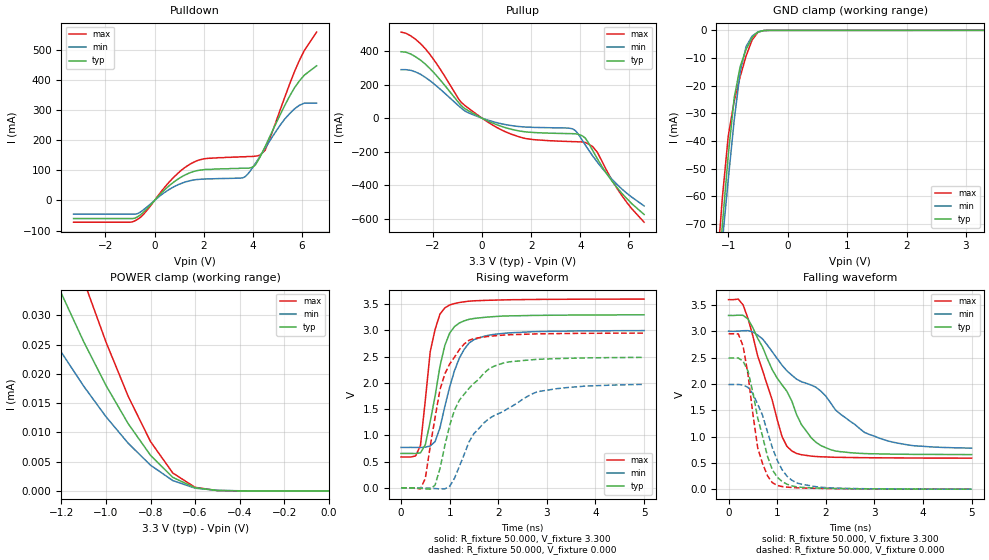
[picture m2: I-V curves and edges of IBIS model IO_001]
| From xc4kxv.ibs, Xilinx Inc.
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|   Model IO_001
[Model]   IO_001
Model_type   I/O
Polarity   Inverting
Enable   Active-High
Vinl =   0.800V
Vinh =   2.000V
Vmeas =   1.650V
Cref =  50.000pF
Rref =   1.000M
Vref =  0.000V
C_comp   7.800pF   6.700pF   8.800pF
[Temperature Range]   50.000   100.000   0.000
[Voltage Range]   3.300V   3.000V   3.600V
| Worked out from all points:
|   slope of the pulldown table from 0 to 0.495 V, typ, clamps not added: 11.9 ohm
|   slope of the pullup table from 0 to 0.495 V, typ, clamps not added: 15 ohm
|   GND clamp passes 1 mA (typ) near -0.52 V on its own axis
|   POWER clamp passes 1 mA (typ) near -2.17 V on its own axis
|   rising waveform, R_fixture 50.000, V_fixture 3.300: 20-80 % time 343ps typ, 429ps min, 251ps max; typ from 0.655 V to 3.3 V
|   rising waveform, R_fixture 50.000, V_fixture 0.000: 20-80 % time 667ps typ, 1.13ns min, 433ps max; typ from 0 V to 2.48 V
|   falling waveform, R_fixture 50.000, V_fixture 3.300: 20-80 % time 876ps typ, 1.66ns min, 567ps max; typ from 3.3 V to 0.659 V
|   falling waveform, R_fixture 50.000, V_fixture 0.000: 20-80 % time 389ps typ, 475ps min, 299ps max; typ from 2.49 V to 0.002 V
[Pulldown]
| voltage   I(typ)   I(min)   I(max)
-3.3V     -60.2mA    -45.6mA    -72.29mA
-900mV    -60.2mA    -45.6mA    -71.15mA
-500mV    -42.78mA   -34.12mA   -50.34mA
700mV     55.86mA    41.45mA    70.07mA
1.5V      93.58mA    66.46mA    123mA
3.6V      107mA      75.22mA    145mA
4V        111mA      110mA      146mA
4.3V      145mA      147mA      151mA
4.5V      178mA      173mA      166mA
5.7V      374mA      304mA      428mA
6.1V      416mA      323mA      498mA
6.6V      447mA      323mA      559mA
[Pullup]
| voltage   I(typ)   I(min)   I(max)
-3.3V     396mA      289mA      513mA
-2.9V     382mA      285mA      490mA
-2.3V     321mA      242mA      412mA
-800mV    68.22mA    54.08mA    87.71mA
400mV     -27.34mA   -18.89mA   -38.44mA
1.7V      -80.31mA   -52.16mA   -119mA
3.6V      -92.22mA   -60.85mA   -139mA
3.8V      -93.34mA   -74.12mA   -140mA
4.1V      -107mA     -136mA     -142mA
4.7V      -243mA     -263mA     -204mA
5.7V      -449mA     -423mA     -463mA
6.6V      -574mA     -523mA     -620mA
[GND_clamp]
| voltage   I(typ)   I(min)   I(max)
-3.3V     -475mA     -431mA     -510mA
-1.2V     -96.91mA   -99.09mA   -88.66mA
-1.1V     -70.47mA   -76.48mA   -60.6mA
-1V       -45.03mA   -53.86mA   -38.11mA
-900mV    -24.36mA   -32.38mA   -25.58mA
-800mV    -13.12mA   -15.05mA   -16.78mA
-700mV    -6.877mA   -5.864mA   -9.257mA
-600mV    -2.638mA   -2.119mA   -3.553mA
-500mV    -566uA     -554uA     -665uA
-400mV    -66.96uA   -103uA     -53.9uA
-300mV    -8.622uA   -14.21uA   -13.77uA
3.3V      2.571nA    15.57nA    666pA
[POWER_clamp]
| voltage   I(typ)   I(min)   I(max)
-3.3V     8.348mA    6.078mA    9.969mA
-1.4V     52.17uA    36.82uA    72.84uA
-1.3V     42.63uA    29.94uA    59.76uA
-1.2V     33.71uA    23.66uA    47.42uA
-1.1V     25.48uA    17.89uA    35.93uA
-1V       18.02uA    12.68uA    25.43uA
-900mV    11.47uA    8.13uA     16.14uA
-800mV    6.082uA    4.396uA    8.428uA
-700mV    2.312uA    1.764uA    3.06uA
-600mV    537nA      470nA      614nA
-500mV    77.35nA    96.49nA    62.62nA
0V        2.571nA    11.85nA    731pA
[Ramp]
| variable   typ   min   max
dV/dt_r   1.491/0.691n   1.183/1.149n   1.769/0.402n
dV/dt_f   1.585/0.880n   1.331/1.666n   1.805/0.536n
R_load = 50.000
[Rising Waveform]
R_fixture = 50.000
V_fixture = 3.300
V_fixture_min = 3.000
V_fixture_max = 3.600
L_fixture = 0.000H
C_fixture = 0.000F
| time   V(typ)   V(min)   V(max)
0s        655mV      770mV      588mV
300ps     654mV      770mV      608mV
400ps     666mV      769mV      809mV
500ps     823mV      775mV      1.678V
600ps     1.265V     798mV      2.595V
700ps     1.746V     881mV      3.018V
900ps     2.711V     1.549V     3.429V
1.2ns     3.142V     2.473V     3.532V
1.5ns     3.227V     2.824V     3.564V
5ns       3.297V     2.996V     3.597V
[Rising Waveform]
R_fixture = 50.000
V_fixture = 0.000
V_fixture_min = 0.000
V_fixture_max = 0.000
L_fixture = 0.000H
C_fixture = 0.000F
| time   V(typ)   V(min)   V(max)
0s        0V         0V         0V
400ps     -8.187mV   -395uV     -20.02mV
500ps     -18.9mV    -3.482mV   183mV
700ps     53.19mV    -13.5mV    1.341V
900ps     801mV      -20.23mV   2.171V
1.1ns     1.481V     183mV      2.491V
1.4ns     1.898V     879mV      2.813V
1.9ns     2.312V     1.37V      2.895V
2.8ns     2.448V     1.828V     2.934V
5ns       2.485V     1.971V     2.948V
[Falling Waveform]
R_fixture = 50.000
V_fixture = 3.300
V_fixture_min = 3.000
V_fixture_max = 3.600
L_fixture = 0.000H
C_fixture = 0.000F
| time   V(typ)   V(min)   V(max)
0s        3.3V       3V         3.6V
300ps     3.302V     3.01V      3.498V
700ps     2.7V       2.854V     2.255V
1.1ns     1.982V     2.356V     1.001V
1.3ns     1.678V     2.167V     729mV
1.7ns     978mV      1.979V     630mV
2.1ns     752mV      1.64V      610mV
2.8ns     678mV      1.078V     600mV
3.2ns     670mV      940mV      597mV
5ns       659mV      782mV      591mV
[Falling Waveform]
R_fixture = 50.000
V_fixture = 0.000
V_fixture_min = 0.000
V_fixture_max = 0.000
L_fixture = 0.000H
C_fixture = 0.000F
| time   V(typ)   V(min)   V(max)
0s        2.492V     1.989V     2.952V
200ps     2.492V     1.99V      2.95V
300ps     2.431V     1.979V     2.717V
400ps     2.243V     1.935V     2.178V
600ps     1.352V     1.613V     785mV
800ps     629mV      1.089V     258mV
900ps     373mV      793mV      127mV
1.2ns     97.08mV    251mV      41.53mV
1.5ns     37.18mV    96.16mV    24.69mV
5ns       2.351mV    2.484mV    2.349mV
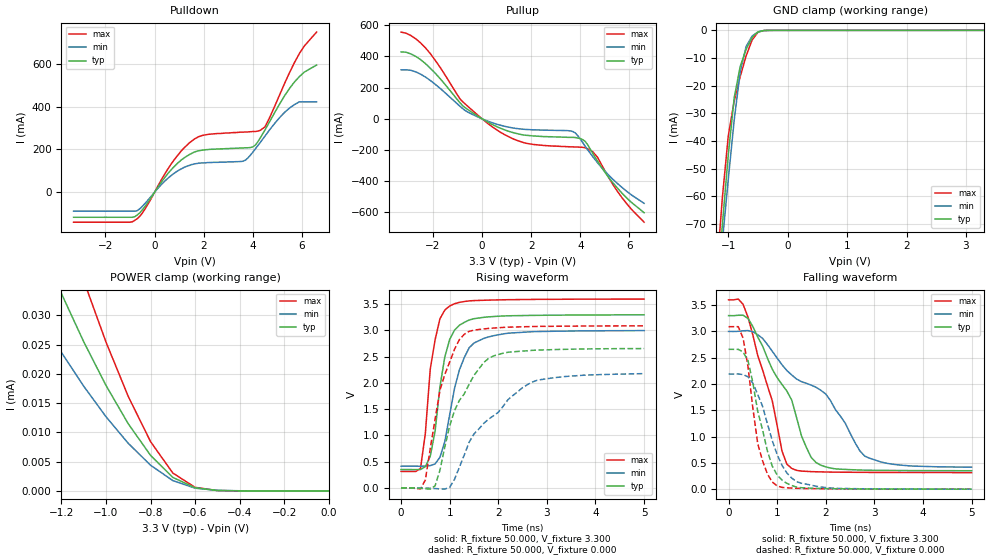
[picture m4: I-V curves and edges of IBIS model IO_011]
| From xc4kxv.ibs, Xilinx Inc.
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|   Model IO_011
[Model]   IO_011
Model_type   I/O
Polarity   Inverting
Enable   Active-High
Vinl =   0.800V
Vinh =   2.000V
Vmeas =   1.650V
Cref =  50.000pF
Rref =   1.000M
Vref =  0.000V
C_comp   7.800pF   6.700pF   8.800pF
[Temperature Range]   50.000   100.000   0.000
[Voltage Range]   3.300V   3.000V   3.600V
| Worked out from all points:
|   slope of the pulldown table from 0 to 0.495 V, typ, clamps not added: 6.14 ohm
|   slope of the pullup table from 0 to 0.495 V, typ, clamps not added: 11.6 ohm
|   GND clamp passes 1 mA (typ) near -0.52 V on its own axis
|   POWER clamp passes 1 mA (typ) near -2.17 V on its own axis
|   rising waveform, R_fixture 50.000, V_fixture 3.300: 20-80 % time 293ps typ, 390ps min, 240ps max; typ from 0.35 V to 3.3 V
|   rising waveform, R_fixture 50.000, V_fixture 0.000: 20-80 % time 645ps typ, 1.06ns min, 451ps max; typ from 0 V to 2.65 V
|   falling waveform, R_fixture 50.000, V_fixture 3.300: 20-80 % time 829ps typ, 1.57ns min, 552ps max; typ from 3.3 V to 0.352 V
|   falling waveform, R_fixture 50.000, V_fixture 0.000: 20-80 % time 391ps typ, 488ps min, 302ps max; typ from 2.66 V to 0.001 V
[Pulldown]
| voltage   I(typ)   I(min)   I(max)
-3.3V     -117mA     -88.65mA   -140mA
-900mV    -117mA     -88.65mA   -138mA
-500mV    -82.83mA   -66.1mA    -97.41mA
700mV     108mA      80.35mA    136mA
1.6V      187mA      132mA      247mA
2.2V      200mA      139mA      271mA
3.6V      207mA      145mA      281mA
4.1V      220mA      202mA      284mA
4.5V      292mA      263mA      306mA
5.7V      516mA      410mA      607mA
6.1V      562mA      423mA      684mA
6.6V      595mA      423mA      749mA
[Pullup]
| voltage   I(typ)   I(min)   I(max)
-3.3V     429mA      314mA      556mA
-2.9V     416mA      311mA      534mA
-2.3V     353mA      267mA      454mA
-900mV    103mA      80.36mA    128mA
600mV     -50.37mA   -34.55mA   -71.3mA
1.8V      -106mA     -68.37mA   -157mA
3.7V      -119mA     -81.84mA   -180mA
4.2V      -145mA     -176mA     -186mA
4.5V      -219mA     -241mA     -210mA
4.7V      -271mA     -281mA     -246mA
5.5V      -442mA     -413mA     -462mA
6.6V      -602mA     -542mA     -663mA
[GND_clamp]
| voltage   I(typ)   I(min)   I(max)
-3.3V     -475mA     -431mA     -510mA
-1.2V     -96.91mA   -99.09mA   -88.66mA
-1.1V     -70.47mA   -76.48mA   -60.6mA
-1V       -45.03mA   -53.86mA   -38.11mA
-900mV    -24.36mA   -32.38mA   -25.58mA
-800mV    -13.12mA   -15.05mA   -16.78mA
-700mV    -6.877mA   -5.864mA   -9.257mA
-600mV    -2.638mA   -2.119mA   -3.553mA
-500mV    -566uA     -554uA     -665uA
-400mV    -66.96uA   -103uA     -53.9uA
-300mV    -8.622uA   -14.21uA   -13.77uA
3.3V      2.571nA    15.57nA    666pA
[POWER_clamp]
| voltage   I(typ)   I(min)   I(max)
-3.3V     8.348mA    6.078mA    9.969mA
-1.4V     52.17uA    36.82uA    72.84uA
-1.3V     42.63uA    29.94uA    59.76uA
-1.2V     33.71uA    23.66uA    47.42uA
-1.1V     25.48uA    17.89uA    35.93uA
-1V       18.02uA    12.68uA    25.43uA
-900mV    11.47uA    8.13uA     16.14uA
-800mV    6.082uA    4.396uA    8.427uA
-700mV    2.312uA    1.764uA    3.06uA
-600mV    537nA      470nA      614nA
-500mV    77.35nA    96.49nA    62.62nA
0V        2.571nA    11.85nA    731pA
[Ramp]
| variable   typ   min   max
dV/dt_r   1.593/0.670n   1.306/1.090n   1.852/0.421n
dV/dt_f   1.769/0.845n   1.548/1.567n   1.970/0.521n
R_load = 50.000
[Rising Waveform]
R_fixture = 50.000
V_fixture = 3.300
V_fixture_min = 3.000
V_fixture_max = 3.600
L_fixture = 0.000H
C_fixture = 0.000F
| time   V(typ)   V(min)   V(max)
0s        350mV      413mV      314mV
400ps     350mV      412mV      368mV
500ps     405mV      414mV      1.041V
600ps     601mV      424mV      2.256V
700ps     1.077V     456mV      2.82V
800ps     1.928V     584mV      3.222V
1ns       2.827V     1.392V     3.465V
1.3ns     3.153V     2.481V     3.55V
1.7ns     3.249V     2.846V     3.574V
5ns       3.297V     2.996V     3.597V
[Rising Waveform]
R_fixture = 50.000
V_fixture = 0.000
V_fixture_min = 0.000
V_fixture_max = 0.000
L_fixture = 0.000H
C_fixture = 0.000F
| time   V(typ)   V(min)   V(max)
0s        0V         0V         0V
400ps     -8.003mV   -603uV     -19.61mV
500ps     -16.94mV   -3.691mV   151mV
700ps     38.44mV    -12.62mV   1.302V
800ps     337mV      -19.46mV   1.86V
1.1ns     1.473V     163mV      2.64V
1.3ns     1.791V     625mV      2.926V
1.8ns     2.466V     1.309V     3.038V
2.7ns     2.62V      2.016V     3.074V
5ns       2.655V     2.176V     3.087V
[Falling Waveform]
R_fixture = 50.000
V_fixture = 3.300
V_fixture_min = 3.000
V_fixture_max = 3.600
L_fixture = 0.000H
C_fixture = 0.000F
| time   V(typ)   V(min)   V(max)
0s        3.3V       3V         3.6V
200ps     3.307V     3.002V     3.615V
400ps     3.247V     3.016V     3.271V
900ps     2.281V     2.622V     1.679V
1.1ns     1.991V     2.365V     724mV
1.3ns     1.694V     2.172V     396mV
1.6ns     797mV      2.014V     340mV
1.9ns     456mV      1.88V      330mV
2.8ns     363mV      631mV      321mV
5ns       352mV      419mV      316mV
[Falling Waveform]
R_fixture = 50.000
V_fixture = 0.000
V_fixture_min = 0.000
V_fixture_max = 0.000
L_fixture = 0.000H
C_fixture = 0.000F
| time   V(typ)   V(min)   V(max)
0s        2.66V      2.19V      3.089V
200ps     2.659V     2.191V     3.09V
300ps     2.608V     2.18V      2.87V
400ps     2.443V     2.137V     2.331V
600ps     1.482V     1.802V     867mV
800ps     725mV      1.24V      288mV
1ns       271mV      657mV      60.67mV
1.3ns     70.53mV    212mV      21.66mV
1.8ns     16.41mV    58.26mV    11.19mV
5ns       1.407mV    1.616mV    1.324mV
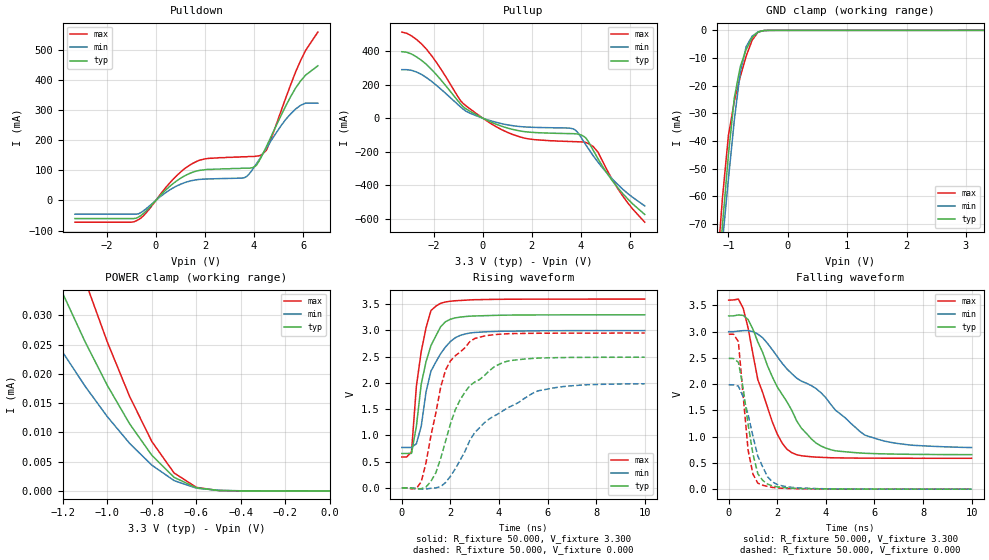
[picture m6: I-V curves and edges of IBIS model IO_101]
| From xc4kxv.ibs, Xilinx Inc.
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|   Model IO_101
[Model]   IO_101
Model_type   I/O
Polarity   Inverting
Enable   Active-High
Vinl =   0.800V
Vinh =   2.000V
Vmeas =   1.650V
Cref =  50.000pF
Rref =   1.000M
Vref =  0.000V
C_comp   7.800pF   6.700pF   8.800pF
[Temperature Range]   50.000   100.000   0.000
[Voltage Range]   3.300V   3.000V   3.600V
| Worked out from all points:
|   slope of the pulldown table from 0 to 0.495 V, typ, clamps not added: 11.9 ohm
|   slope of the pullup table from 0 to 0.495 V, typ, clamps not added: 15 ohm
|   GND clamp passes 1 mA (typ) near -0.52 V on its own axis
|   POWER clamp passes 1 mA (typ) near -2.17 V on its own axis
|   rising waveform, R_fixture 50.000, V_fixture 3.300: 20-80 % time 661ps typ, 780ps min, 493ps max; typ from 0.655 V to 3.3 V
|   rising waveform, R_fixture 50.000, V_fixture 0.000: 20-80 % time 1.37ns typ, 2.4ns min, 893ps max; typ from 0 V to 2.49 V
|   falling waveform, R_fixture 50.000, V_fixture 3.300: 20-80 % time 1.73ns typ, 3.13ns min, 1.05ns max; typ from 3.3 V to 0.658 V
|   falling waveform, R_fixture 50.000, V_fixture 0.000: 20-80 % time 522ps typ, 732ps min, 382ps max; typ from 2.49 V to 0.001 V
[Pulldown]
| voltage   I(typ)   I(min)   I(max)
-3.3V     -60.2mA    -45.6mA    -72.29mA
-900mV    -60.2mA    -45.6mA    -71.15mA
-500mV    -42.78mA   -34.12mA   -50.34mA
700mV     55.86mA    41.45mA    70.07mA
1.5V      93.58mA    66.46mA    123mA
3.6V      107mA      75.22mA    145mA
4V        111mA      110mA      146mA
4.3V      145mA      147mA      151mA
4.5V      178mA      173mA      166mA
5.7V      374mA      304mA      428mA
6.1V      416mA      323mA      498mA
6.6V      447mA      323mA      559mA
[Pullup]
| voltage   I(typ)   I(min)   I(max)
-3.3V     396mA      289mA      513mA
-2.9V     382mA      285mA      490mA
-2.3V     321mA      242mA      412mA
-800mV    68.22mA    54.08mA    87.71mA
400mV     -27.34mA   -18.89mA   -38.44mA
1.7V      -80.31mA   -52.16mA   -119mA
3.6V      -92.22mA   -60.85mA   -139mA
3.8V      -93.34mA   -74.12mA   -140mA
4.1V      -107mA     -136mA     -142mA
4.7V      -243mA     -263mA     -204mA
5.7V      -449mA     -423mA     -463mA
6.6V      -574mA     -523mA     -620mA
[GND_clamp]
| voltage   I(typ)   I(min)   I(max)
-3.3V     -475mA     -431mA     -510mA
-1.2V     -96.9mA    -99.09mA   -88.66mA
-1.1V     -70.47mA   -76.48mA   -60.6mA
-1V       -45.03mA   -53.86mA   -38.11mA
-900mV    -24.36mA   -32.38mA   -25.58mA
-800mV    -13.12mA   -15.05mA   -16.78mA
-700mV    -6.877mA   -5.864mA   -9.257mA
-600mV    -2.638mA   -2.119mA   -3.553mA
-500mV    -566uA     -554uA     -665uA
-400mV    -66.96uA   -103uA     -53.9uA
-300mV    -8.622uA   -14.21uA   -13.77uA
3.3V      2.571nA    15.57nA    666pA
[POWER_clamp]
| voltage   I(typ)   I(min)   I(max)
-3.3V     8.348mA    6.078mA    9.967mA
-1.4V     52.17uA    36.82uA    72.84uA
-1.3V     42.63uA    29.94uA    59.76uA
-1.2V     33.71uA    23.66uA    47.42uA
-1.1V     25.48uA    17.89uA    35.93uA
-1V       18.02uA    12.68uA    25.43uA
-900mV    11.47uA    8.13uA     16.14uA
-800mV    6.082uA    4.396uA    8.427uA
-700mV    2.312uA    1.764uA    3.06uA
-600mV    537nA      470nA      614nA
-500mV    77.35nA    96.49nA    62.62nA
0V        2.571nA    11.85nA    731pA
[Ramp]
| variable   typ   min   max
dV/dt_r   1.494/1.416n   1.190/2.435n   1.771/0.820n
dV/dt_f   1.585/1.733n   1.324/3.127n   1.807/0.991n
R_load = 50.000
[Rising Waveform]
R_fixture = 50.000
V_fixture = 3.300
V_fixture_min = 3.000
V_fixture_max = 3.600
L_fixture = 0.000H
C_fixture = 0.000F
| time   V(typ)   V(min)   V(max)
0s        655mV      770mV      588mV
400ps     657mV      770mV      687mV
600ps     1.171V     840mV      1.935V
800ps     1.979V     1.173V     2.6V
1ns       2.409V     1.834V     3.057V
1.2ns     2.712V     2.225V     3.38V
1.4ns     2.894V     2.397V     3.463V
1.8ns     3.167V     2.686V     3.544V
2.8ns     3.273V     2.952V     3.583V
10ns      3.299V     2.998V     3.599V
[Rising Waveform]
R_fixture = 50.000
V_fixture = 0.000
V_fixture_min = 0.000
V_fixture_max = 0.000
L_fixture = 0.000H
C_fixture = 0.000F
| time   V(typ)   V(min)   V(max)
0s        0V         0V         0V
600ps     -23.76mV   -8.017mV   -10.15mV
800ps     -15.86mV   -25.32mV   115mV
1.2ns     124mV      -9.189mV   998mV
1.8ns     886mV      100mV      2.246V
2.2ns     1.484V     362mV      2.517V
2.8ns     1.947V     905mV      2.788V
4.2ns     2.395V     1.479V     2.934V
5.6ns     2.473V     1.848V     2.947V
10ns      2.49V      1.984V     2.951V
[Falling Waveform]
R_fixture = 50.000
V_fixture = 3.300
V_fixture_min = 3.000
V_fixture_max = 3.600
L_fixture = 0.000H
C_fixture = 0.000F
| time   V(typ)   V(min)   V(max)
0s        3.3V       3V         3.6V
400ps     3.319V     3.011V     3.621V
600ps     3.31V      3.02V      3.444V
1.2ns     2.804V     2.954V     2.085V
2ns       1.948V     2.526V     1.05V
2.6ns     1.501V     2.199V     695mV
3ns       1.158V     2.056V     637mV
3.8ns     822mV      1.837V     607mV
5.6ns     684mV      1.032V     591mV
10ns      658mV      793mV      589mV
[Falling Waveform]
R_fixture = 50.000
V_fixture = 0.000
V_fixture_min = 0.000
V_fixture_max = 0.000
L_fixture = 0.000H
C_fixture = 0.000F
| time   V(typ)   V(min)   V(max)
0s        2.492V     1.989V     2.952V
200ps     2.489V     1.988V     2.951V
400ps     2.419V     1.962V     2.809V
600ps     1.915V     1.754V     1.76V
800ps     1.234V     1.421V     744mV
1ns       667mV      1.007V     287mV
1.2ns     296mV      628mV      115mV
1.8ns     63.59mV    138mV      34.04mV
2.4ns     25.52mV    46.18mV    14.9mV
10ns      770uV      917uV      669uV
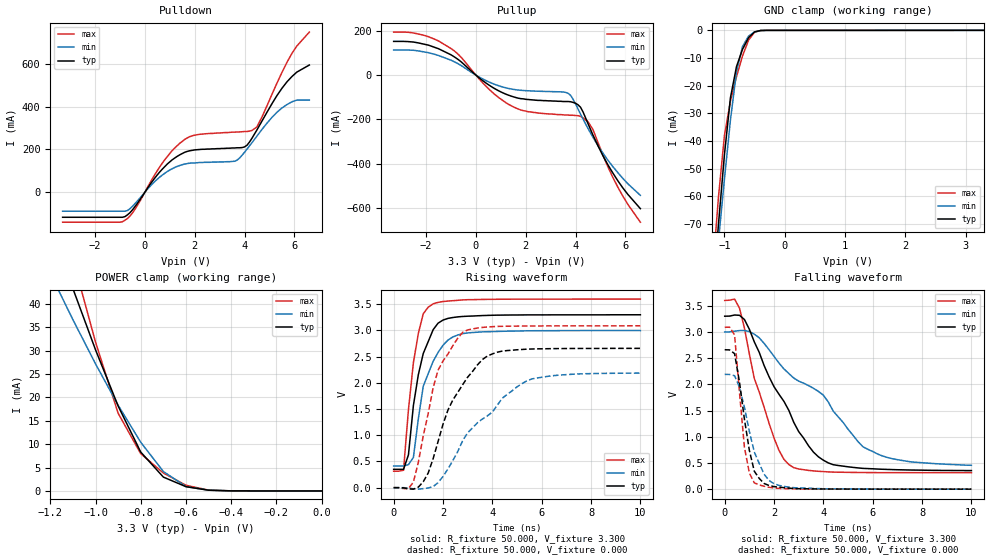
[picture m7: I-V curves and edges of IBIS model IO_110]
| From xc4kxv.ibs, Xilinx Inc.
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|   Model IO_110
[Model]   IO_110
Model_type   I/O
Polarity   Inverting
Enable   Active-High
Vinl =   0.800V
Vinh =   2.000V
Vmeas =   1.650V
Cref =  50.000pF
Rref =   1.000M
Vref =  0.000V
C_comp   7.800pF   6.700pF   8.800pF
[Temperature Range]   50.000   100.000   0.000
[Voltage Range]   3.300V   3.000V   3.600V
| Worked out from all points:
|   slope of the pulldown table from 0 to 0.495 V, typ, clamps not added: 6.14 ohm
|   slope of the pullup table from 0 to 0.495 V, typ, clamps not added: 11.6 ohm
|   GND clamp passes 1 mA (typ) near -0.52 V on its own axis
|   POWER clamp passes 1 mA (typ) near -0.60 V on its own axis
|   rising waveform, R_fixture 50.000, V_fixture 3.300: 20-80 % time 665ps typ, 787ps min, 489ps max; typ from 0.35 V to 3.3 V
|   rising waveform, R_fixture 50.000, V_fixture 0.000: 20-80 % time 1.45ns typ, 2.22ns min, 1.03ns max; typ from 0 V to 2.66 V
|   falling waveform, R_fixture 50.000, V_fixture 3.300: 20-80 % time 1.94ns typ, 3.24ns min, 1.15ns max; typ from 3.3 V to 0.355 V
|   falling waveform, R_fixture 50.000, V_fixture 0.000: 20-80 % time 537ps typ, 751ps min, 388ps max; typ from 2.66 V to 0.001 V
[Pulldown]
| voltage   I(typ)   I(min)   I(max)
-3.3V     -117mA     -88.65mA   -140mA
-900mV    -117mA     -88.65mA   -138mA
-500mV    -82.83mA   -66.1mA    -97.41mA
700mV     108mA      80.35mA    136mA
1.6V      187mA      132mA      247mA
2.2V      200mA      139mA      271mA
3.6V      207mA      145mA      281mA
4.1V      220mA      202mA      284mA
4.5V      292mA      263mA      306mA
5.5V      486mA      394mA      560mA
6.1V      562mA      431mA      684mA
6.6V      595mA      431mA      749mA
[Pullup]
| voltage   I(typ)   I(min)   I(max)
-3.3V     152mA      113mA      194mA
-2.1V     140mA      105mA      180mA
-1V       91.6mA     67.32mA    120mA
600mV     -50.37mA   -34.55mA   -71.3mA
1.5V      -97.65mA   -64.19mA   -143mA
3.6V      -119mA     -77.86mA   -180mA
3.8V      -120mA     -91.24mA   -181mA
4.1V      -134mA     -153mA     -183mA
4.5V      -219mA     -241mA     -210mA
4.7V      -271mA     -281mA     -246mA
5.7V      -477mA     -440mA     -506mA
6.6V      -602mA     -542mA     -663mA
[GND_clamp]
| voltage   I(typ)   I(min)   I(max)
-3.3V     -475mA     -431mA     -510mA
-1.2V     -96.91mA   -99.09mA   -88.66mA
-1.1V     -70.47mA   -76.48mA   -60.6mA
-1V       -45.03mA   -53.86mA   -38.11mA
-900mV    -24.36mA   -32.38mA   -25.58mA
-800mV    -13.12mA   -15.05mA   -16.78mA
-700mV    -6.877mA   -5.864mA   -9.257mA
-600mV    -2.638mA   -2.119mA   -3.553mA
-500mV    -566uA     -554uA     -665uA
-400mV    -66.96uA   -103uA     -53.9uA
-300mV    -8.622uA   -14.21uA   -13.77uA
3.3V      2.515nA    1.988uA    642pA
[POWER_clamp]
| voltage   I(typ)   I(min)   I(max)
-3.3V     290mA      209mA      377mA
-1.2V     56.94mA    46.52mA    68.27mA
-1.1V     43.28mA    36.64mA    49.6mA
-1V       30.2mA     27.19mA    31.86mA
-900mV    18.17mA    18.33mA    16.62mA
-800mV    8.311mA    10.41mA    7.969mA
-700mV    2.958mA    4.154mA    3.831mA
-600mV    907uA      937uA      1.207mA
-500mV    155uA      152uA      171uA
-400mV    15.39uA    19.38uA    11.33uA
0V        2.515nA    11.62nA    717pA
[Ramp]
| variable   typ   min   max
dV/dt_r   1.595/1.489n   1.312/2.285n   1.853/0.973n
dV/dt_f   1.767/1.915n   1.526/3.261n   1.971/1.100n
R_load = 50.000
[Rising Waveform]
R_fixture = 50.000
V_fixture = 3.300
V_fixture_min = 3.000
V_fixture_max = 3.600
L_fixture = 0.000H
C_fixture = 0.000F
| time   V(typ)   V(min)   V(max)
0s        350mV      413mV      314mV
400ps     349mV      413mV      333mV
600ps     627mV      440mV      1.491V
800ps     1.567V     576mV      2.383V
1ns       2.155V     1.313V     2.943V
1.2ns     2.561V     1.936V     3.32V
1.4ns     2.786V     2.175V     3.444V
1.8ns     3.139V     2.58V      3.536V
2.8ns     3.267V     2.94V      3.583V
10ns      3.299V     2.998V     3.599V
[Rising Waveform]
R_fixture = 50.000
V_fixture = 0.000
V_fixture_min = 0.000
V_fixture_max = 0.000
L_fixture = 0.000H
C_fixture = 0.000F
| time   V(typ)   V(min)   V(max)
0s        0V         0V         0V
800ps     -28.7mV    -22.19mV   107mV
1.4ns     279mV      -6.638mV   1.415V
1.8ns     879mV      95.17mV    2.242V
2.2ns     1.48V      357mV      2.55V
2.8ns     1.967V     900mV      2.965V
3.8ns     2.512V     1.37V      3.066V
4.4ns     2.606V     1.706V     3.079V
5.6ns     2.646V     2.075V     3.086V
10ns      2.658V     2.186V     3.089V
[Falling Waveform]
R_fixture = 50.000
V_fixture = 3.300
V_fixture_min = 3.000
V_fixture_max = 3.600
L_fixture = 0.000H
C_fixture = 0.000F
| time   V(typ)   V(min)   V(max)
0s        3.3V       3V         3.6V
600ps     3.317V     3.026V     3.453V
1.2ns     2.81V      2.957V     2.112V
2ns       1.955V     2.533V     976mV
2.6ns     1.503V     2.206V     470mV
3.6ns     706mV      1.924V     349mV
4.4ns     467mV      1.489V     326mV
5.6ns     397mV      811mV      318mV
6.4ns     380mV      633mV      316mV
10ns      355mV      456mV      315mV
[Falling Waveform]
R_fixture = 50.000
V_fixture = 0.000
V_fixture_min = 0.000
V_fixture_max = 0.000
L_fixture = 0.000H
C_fixture = 0.000F
| time   V(typ)   V(min)   V(max)
0s        2.66V      2.19V      3.089V
200ps     2.657V     2.189V     3.09V
400ps     2.586V     2.165V     2.943V
600ps     2.04V      1.943V     1.842V
800ps     1.334V     1.561V     800mV
1ns       740mV      1.101V     308mV
1.2ns     343mV      709mV      121mV
1.8ns     70.16mV    164mV      36.05mV
2.4ns     29.75mV    52.91mV    11.2mV
10ns      535uV      755uV      415uV
